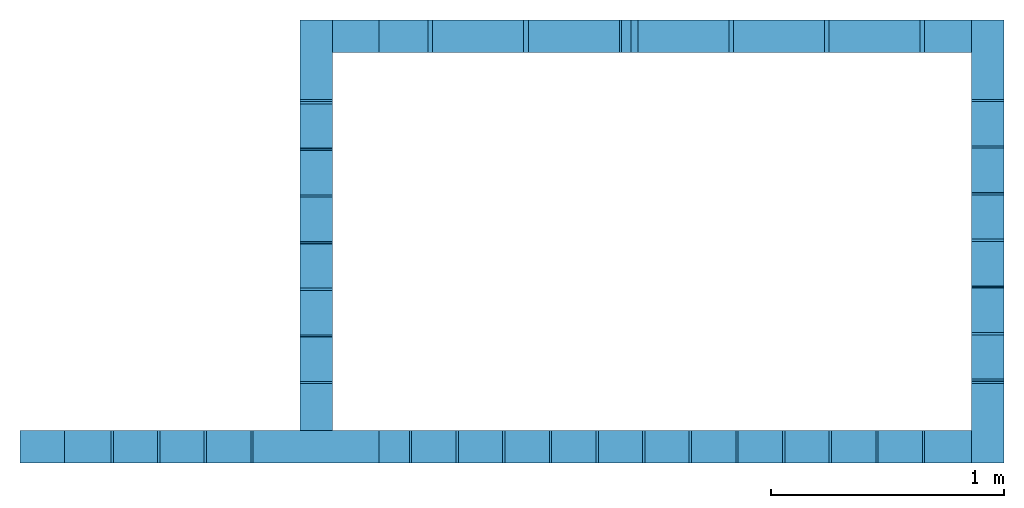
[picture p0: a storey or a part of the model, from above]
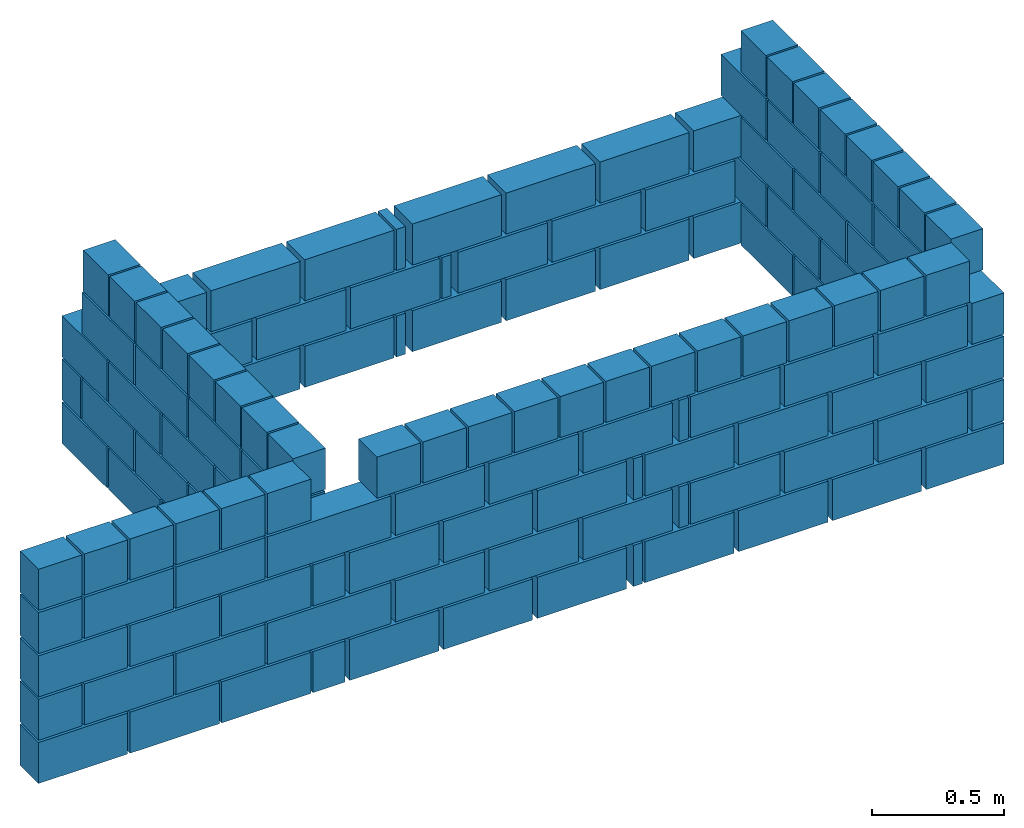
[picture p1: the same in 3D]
Properties of the parts of a building model (IFC4)

# File
Description: IFC4
Time: 2022-03-09T15:24:39
Made in: IfcPlusPlus

# IfcBuildingStorey (4)
Name | LongName | Elevation (cm)
PISO | PISO | 0
LAJE | LAJE | 272
RESP1 | RESP1 | 372
RESP2 | RESP2 | 432

# IfcWall (99)
Name | In | Armaduras - Aço CA50 - ø10.0mm | Argamassas e Grautes - Argamassa de assentamento - 3MPa (m3) | Argamassas e Grautes - Graute - 15MPa (m3) | Blocos de concreto - Classe B - Família 14x39x19 - 4MPa - Inteiro - 14x39x19
19 x  | PISO | 1
3 x  | PISO | Pset_AltoQi_QiBuilder-Itens_Associados - Description: Lista de insumos associados ao elemento
PAR-PISO-1 | PISO | 1 | 0.03616 | 0.057017 | 18 | Pset_AltoQi_QiBuilder-Itens_Associados - Armaduras - Aço CA50 - ø8.0mm: 1; Blocos de concreto - Classe B - Família 14x39x19 - 4MPa - Contrafiamento "L" - 14x34x19: 6; Blocos de concreto - Classe B - Família 14x39x19 - 4MPa - Meio Canaleta J Alto - 14x19x31x19: 4; Blocos de concreto - Classe B - Família 14x39x19 - 4MPa - Meio bloco - 14x19x19: 6
PAR-PISO-1 | PISO |  | 0.010368 | 0.046106 | Pset_AltoQi_QiBuilder-Itens_Associados - Blocos de concreto - Classe B - Família 14x39x19 - 4MPa - Meio Canaleta J Alto - 14x19x31x19: 9; Blocos de concreto - Classe B - Família 14x39x19 - 4MPa - Meio bloco - 14x19x19: 6; Blocos de concreto - Classe B - Família 14x39x19 - 4MPa - Pastilha - 14x04x19: 6
PAR-PISO-10 | PISO |  | 0.089728 | 0.14329 | 29 | Pset_AltoQi_QiBuilder-Itens_Associados - Armaduras - Aço CA50 - ø8.0mm: 1; Blocos de concreto - Classe B - Família 14x39x19 - 4MPa - Contrafiamento "L" - 14x34x19: 22; Blocos de concreto - Classe B - Família 14x39x19 - 4MPa - Meio Canaleta J Alto - 14x19x31x19: 13; Blocos de concreto - Classe B - Família 14x39x19 - 4MPa - Meio Canaleta - 14x19x19: 28; Blocos de concreto - Classe B - Família 14x39x19 - 4MPa - Pastilha - 14x09x19: 6
PAR-PISO-10 | PISO |  | 0.016 | 0.066203 | 2 | Pset_AltoQi_QiBuilder-Itens_Associados - Armaduras - Aço CA50 - ø8.0mm: 1; Blocos de concreto - Classe B - Família 14x39x19 - 4MPa - Meio Canaleta J Alto - 14x19x31x19: 5; Blocos de concreto - Classe B - Família 14x39x19 - 4MPa - Meio bloco - 14x19x19: 11; Blocos de concreto - Classe B - Família 14x39x19 - 4MPa - Meio Canaleta - 14x19x19: 5
PAR-PISO-11 | PISO |  | 0.048768 | 0.08207 | 30 | Pset_AltoQi_QiBuilder-Itens_Associados - Blocos de concreto - Classe B - Família 14x39x19 - 4MPa - Contrafiamento "L" - 14x34x19: 6; Blocos de concreto - Classe B - Família 14x39x19 - 4MPa - Meio Canaleta J Alto - 14x19x31x19: 6
PAR-PISO-11 | PISO |  | 0.14048 | 0.068193 | 96 | Pset_AltoQi_QiBuilder-Itens_Associados - Armaduras - Aço CA50 - ø8.0mm: 2; Blocos de concreto - Classe B - Família 14x39x19 - 4MPa - Contrafiamento "L" - 14x34x19: 6; Blocos de concreto - Classe B - Família 14x39x19 - 4MPa - Meio Canaleta J Alto - 14x19x31x19: 17
PAR-PISO-11 | PISO |  | 0.11232 | 0.106628 | 72 | Pset_AltoQi_QiBuilder-Itens_Associados - Blocos de concreto - Classe B - Família 14x39x19 - 4MPa - Meio Canaleta J Alto - 14x19x31x19: 14; Blocos de concreto - Classe B - Família 14x39x19 - 4MPa - Meio bloco - 14x19x19: 1; Blocos de concreto - Classe B - Família 14x39x19 - 4MPa - Contrafiamento "T" - 14x54x19: 6
PAR-PISO-11 | PISO |  | 0.03088 | 0.058396 | 6 | Pset_AltoQi_QiBuilder-Itens_Associados - Blocos de concreto - Classe B - Família 14x39x19 - 4MPa - Meio Canaleta J Alto - 14x19x31x19: 2; Blocos de concreto - Classe B - Família 14x39x19 - 4MPa - Pastilha - 14x04x19: 6; Blocos de concreto - Classe B - Família 14x39x19 - 4MPa - Pastilha - 14x09x19: 5; Blocos de concreto - Classe B - Família 14x39x19 - 4MPa - Contrafiamento "T" - 14x54x19: 11
PAR-PISO-12 | PISO |  | 0.09008 | 0.053939 | 59 | Pset_AltoQi_QiBuilder-Itens_Associados - Blocos de concreto - Classe B - Família 14x39x19 - 4MPa - Contrafiamento "L" - 14x34x19: 5; Blocos de concreto - Classe B - Família 14x39x19 - 4MPa - Meio Canaleta - 14x19x19: 14
PAR-PISO-12 | PISO |  | 0.01456 | 0.014794 | 6 | Pset_AltoQi_QiBuilder-Itens_Associados - Armaduras - Aço CA50 - ø8.0mm: 1; Blocos de concreto - Classe B - Família 14x39x19 - 4MPa - Contrafiamento "L" - 14x34x19: 5; Blocos de concreto - Classe B - Família 14x39x19 - 4MPa - Meio bloco - 14x19x19: 1; Blocos de concreto - Classe B - Família 14x39x19 - 4MPa - Meio Canaleta - 14x19x19: 1
PAR-PISO-12 | PISO |  | 0.011456 | 0.061622 | Pset_AltoQi_QiBuilder-Itens_Associados - Armaduras - Aço CA50 - ø8.0mm: 1; Blocos de concreto - Classe B - Família 14x39x19 - 4MPa - Meio bloco - 14x19x19: 6; Blocos de concreto - Classe B - Família 14x39x19 - 4MPa - Pastilha - 14x04x19: 5; Blocos de concreto - Classe B - Família 14x39x19 - 4MPa - Meio Canaleta - 14x19x19: 11
PAR-PISO-13 | PISO |  | 0.04864 | 0.026598 | 24 | Pset_AltoQi_QiBuilder-Itens_Associados - Blocos de concreto - Classe B - Família 14x39x19 - 4MPa - Contrafiamento "L" - 14x34x19: 12; Blocos de concreto - Classe B - Família 14x39x19 - 4MPa - Meio bloco - 14x19x19: 1; Blocos de concreto - Classe B - Família 14x39x19 - 4MPa - Meio Canaleta - 14x19x19: 6
PAR-PISO-13 | PISO | 1 | 0.02816 | 0.08143 | 6 | Pset_AltoQi_QiBuilder-Itens_Associados - Armaduras - Aço CA50 - ø8.0mm: 1; Blocos de concreto - Classe B - Família 14x39x19 - 4MPa - Contrafiamento "L" - 14x34x19: 6; Blocos de concreto - Classe B - Família 14x39x19 - 4MPa - Meio Canaleta J Alto - 14x19x31x19: 2; Blocos de concreto - Classe B - Família 14x39x19 - 4MPa - Pastilha - 14x04x19: 12; Blocos de concreto - Classe B - Família 14x39x19 - 4MPa - Contrafiamento "T" - 14x54x19: 6
PAR-PISO-13 | PISO |  | 0.04304 | 0.038986 | 18 | Pset_AltoQi_QiBuilder-Itens_Associados - Blocos de concreto - Classe B - Família 14x39x19 - 4MPa - Contrafiamento "L" - 14x34x19: 5; Blocos de concreto - Classe B - Família 14x39x19 - 4MPa - Meio bloco - 14x19x19: 1; Blocos de concreto - Classe B - Família 14x39x19 - 4MPa - Pastilha - 14x04x19: 11; Blocos de concreto - Classe B - Família 14x39x19 - 4MPa - Meio Canaleta - 14x19x19: 4; Blocos de concreto - Classe B - Família 14x39x19 - 4MPa - Contrafiamento "T" - 14x54x19: 5; Blocos de concreto - Classe B - Família 14x39x19 - 4MPa - Contrafiamento compensador - 14x24x19: 1
PAR-PISO-14 | PISO | 1 | 0.037888 | 0.116429 | 6 | Pset_AltoQi_QiBuilder-Itens_Associados - Armaduras - Aço CA50 - ø8.0mm: 1; Blocos de concreto - Classe B - Família 14x39x19 - 4MPa - Contrafiamento "L" - 14x34x19: 11; Blocos de concreto - Classe B - Família 14x39x19 - 4MPa - Meio bloco - 14x19x19: 11; Blocos de concreto - Classe B - Família 14x39x19 - 4MPa - Pastilha - 14x04x19: 5; Blocos de concreto - Classe B - Família 14x39x19 - 4MPa - Meio Canaleta - 14x19x19: 16
PAR-PISO-15 | PISO |  | 0.078848 | 0.132438 | 28 | Pset_AltoQi_QiBuilder-Itens_Associados - Armaduras - Aço CA50 - ø8.0mm: 1; Blocos de concreto - Classe B - Família 14x39x19 - 4MPa - Contrafiamento "L" - 14x34x19: 5; Blocos de concreto - Classe B - Família 14x39x19 - 4MPa - Meio Canaleta J Alto - 14x19x31x19: 12; Blocos de concreto - Classe B - Família 14x39x19 - 4MPa - Pastilha - 14x04x19: 6; Blocos de concreto - Classe B - Família 14x39x19 - 4MPa - Meio Canaleta - 14x19x19: 24; Blocos de concreto - Classe B - Família 14x39x19 - 4MPa - Contrafiamento "T" - 14x54x19: 5; Blocos de concreto - Classe B - Família 14x39x19 - 4MPa - Contrafiamento compensador - 14x24x19: 6
PAR-PISO-15 | PISO |  | 0.07792 | 0.134534 | 28 | Pset_AltoQi_QiBuilder-Itens_Associados - Armaduras - Aço CA50 - ø8.0mm: 3; Blocos de concreto - Classe B - Família 14x39x19 - 4MPa - Contrafiamento "L" - 14x34x19: 6; Blocos de concreto - Classe B - Família 14x39x19 - 4MPa - Meio Canaleta J Alto - 14x19x31x19: 12; Blocos de concreto - Classe B - Família 14x39x19 - 4MPa - Pastilha - 14x04x19: 6; Blocos de concreto - Classe B - Família 14x39x19 - 4MPa - Meio Canaleta - 14x19x19: 24; Blocos de concreto - Classe B - Família 14x39x19 - 4MPa - Pastilha - 14x09x19: 1; Blocos de concreto - Classe B - Família 14x39x19 - 4MPa - Contrafiamento "T" - 14x54x19: 4; Blocos de concreto - Classe B - Família 14x39x19 - 4MPa - Contrafiamento compensador - 14x24x19: 5
PAR-PISO-15 | PISO |  | 0.0512 | 0.08223 | 26 | Pset_AltoQi_QiBuilder-Itens_Associados - Armaduras - Aço CA50 - ø8.0mm: 1; Blocos de concreto - Classe B - Família 14x39x19 - 4MPa - Meio Canaleta J Alto - 14x19x31x19: 8; Blocos de concreto - Classe B - Família 14x39x19 - 4MPa - Meio bloco - 14x19x19: 3; Blocos de concreto - Classe B - Família 14x39x19 - 4MPa - Meio Canaleta - 14x19x19: 17
PAR-PISO-2 | PISO |  | 0.163648 | 0.103037 | 108 | Pset_AltoQi_QiBuilder-Itens_Associados - Armaduras - Aço CA50 - ø8.0mm: 1; Blocos de concreto - Classe B - Família 14x39x19 - 4MPa - Contrafiamento "L" - 14x34x19: 12; Blocos de concreto - Classe B - Família 14x39x19 - 4MPa - Meio Canaleta J Alto - 14x19x31x19: 19
PAR-PISO-3 | PISO |  | 0.011744 |  | 5 | Pset_AltoQi_QiBuilder-Itens_Associados - Blocos de concreto - Classe B - Família 14x39x19 - 4MPa - Contrafiamento "L" - 14x34x19: 3; Blocos de concreto - Classe B - Família 14x39x19 - 4MPa - Meio bloco - 14x19x19: 2; Blocos de concreto - Classe B - Família 14x39x19 - 4MPa - Pastilha - 14x04x19: 5
PAR-PISO-4 | PISO | 1 | 0.055776 | 0.178548 | 10 | Pset_AltoQi_QiBuilder-Itens_Associados - Armaduras - Aço CA50 - ø8.0mm: 2; Blocos de concreto - Classe B - Família 14x39x19 - 4MPa - Contrafiamento "L" - 14x34x19: 6; Blocos de concreto - Classe B - Família 14x39x19 - 4MPa - Meio bloco - 14x19x19: 14; Blocos de concreto - Classe B - Família 14x39x19 - 4MPa - Pastilha - 14x04x19: 11; Blocos de concreto - Classe B - Família 14x39x19 - 4MPa - Meio Canaleta - 14x19x19: 35; Blocos de concreto - Classe B - Família 14x39x19 - 4MPa - Pastilha - 14x09x19: 3; Blocos de concreto - Classe B - Família 14x39x19 - 4MPa - Contrafiamento compensador - 14x24x19: 3
PAR-PISO-5 | PISO |  | 0.018816 | 0.070844 | 5 | Pset_AltoQi_QiBuilder-Itens_Associados - Armaduras - Aço CA50 - ø8.0mm: 1; Blocos de concreto - Classe B - Família 14x39x19 - 4MPa - Meio bloco - 14x19x19: 6; Blocos de concreto - Classe B - Família 14x39x19 - 4MPa - Pastilha - 14x04x19: 11; Blocos de concreto - Classe B - Família 14x39x19 - 4MPa - Meio Canaleta - 14x19x19: 11
PAR-PISO-5 | PISO | 1 | 0.10768 | 0.175331 | 64 | Pset_AltoQi_QiBuilder-Itens_Associados - Armaduras - Aço CA50 - ø8.0mm: 2; Blocos de concreto - Classe B - Família 14x39x19 - 4MPa - Contrafiamento "L" - 14x34x19: 5; Blocos de concreto - Classe B - Família 14x39x19 - 4MPa - Meio bloco - 14x19x19: 1; Blocos de concreto - Classe B - Família 14x39x19 - 4MPa - Pastilha - 14x04x19: 9; Blocos de concreto - Classe B - Família 14x39x19 - 4MPa - Meio Canaleta - 14x19x19: 27; Blocos de concreto - Classe B - Família 14x39x19 - 4MPa - Contrafiamento compensador - 14x24x19: 1
PAR-PISO-6 | PISO |  | 0.01904 | 0.074906 | 5 | Pset_AltoQi_QiBuilder-Itens_Associados - Armaduras - Aço CA50 - ø8.0mm: 2; Blocos de concreto - Classe B - Família 14x39x19 - 4MPa - Meio bloco - 14x19x19: 6; Blocos de concreto - Classe B - Família 14x39x19 - 4MPa - Pastilha - 14x04x19: 11; Blocos de concreto - Classe B - Família 14x39x19 - 4MPa - Meio Canaleta - 14x19x19: 11
PAR-PISO-6 | PISO | 1 | 0.109568 | 0.134617 | 72 | Pset_AltoQi_QiBuilder-Itens_Associados - Blocos de concreto - Classe B - Família 14x39x19 - 4MPa - Contrafiamento "L" - 14x34x19: 6; Blocos de concreto - Classe B - Família 14x39x19 - 4MPa - Pastilha - 14x04x19: 12; Blocos de concreto - Classe B - Família 14x39x19 - 4MPa - Meio Canaleta - 14x19x19: 14
PAR-PISO-7 | PISO |  | 0.035776 | 0.025324 | 18 | Pset_AltoQi_QiBuilder-Itens_Associados - Armaduras - Aço CA50 - ø8.0mm: 1; Blocos de concreto - Classe B - Família 14x39x19 - 4MPa - Contrafiamento "L" - 14x34x19: 6; Blocos de concreto - Classe B - Família 14x39x19 - 4MPa - Meio bloco - 14x19x19: 6; Blocos de concreto - Classe B - Família 14x39x19 - 4MPa - Meio Canaleta - 14x19x19: 4
PAR-PISO-8 | PISO |  | 0.01344 |  | 8 | Pset_AltoQi_QiBuilder-Itens_Associados - Blocos de concreto - Classe B - Família 14x39x19 - 4MPa - Meio bloco - 14x19x19: 2; Blocos de concreto - Classe B - Família 14x39x19 - 4MPa - Pastilha - 14x04x19: 3; Blocos de concreto - Classe B - Família 14x39x19 - 4MPa - Contrafiamento compensador - 14x24x19: 2
PAR-PISO-9 | PISO | 1 | 0.13536 | 0.09114 | 72 | Pset_AltoQi_QiBuilder-Itens_Associados - Armaduras - Aço CA50 - ø8.0mm: 1; Blocos de concreto - Classe B - Família 14x39x19 - 4MPa - Contrafiamento "L" - 14x34x19: 30; Blocos de concreto - Classe B - Família 14x39x19 - 4MPa - Meio Canaleta J Alto - 14x19x31x19: 15
PAR-PISO-9 | PISO |  | 0.032128 | 0.029051 | 18 | Pset_AltoQi_QiBuilder-Itens_Associados - Blocos de concreto - Classe B - Família 14x39x19 - 4MPa - Contrafiamento "L" - 14x34x19: 6; Blocos de concreto - Classe B - Família 14x39x19 - 4MPa - Meio Canaleta - 14x19x19: 4
9 x  | LAJE | 1
2 x  | LAJE | Pset_AltoQi_QiBuilder-Itens_Associados - Description: Lista de insumos associados ao elemento
PAR-LAJE-1 | LAJE |  | 0.044096 | 0.059454 | 24 | Pset_AltoQi_QiBuilder-Itens_Associados - Armaduras - Aço CA50 - ø8.0mm: 1; Blocos de concreto - Classe B - Família 14x39x19 - 4MPa - Contrafiamento "L" - 14x34x19: 4; Blocos de concreto - Classe B - Família 14x39x19 - 4MPa - Pastilha - 14x04x19: 4; Blocos de concreto - Classe B - Família 14x39x19 - 4MPa - Meio Canaleta - 14x19x19: 13
PAR-LAJE-2 | LAJE |  | 0.041856 | 0.04925 | 24 | Pset_AltoQi_QiBuilder-Itens_Associados - Blocos de concreto - Classe B - Família 14x39x19 - 4MPa - Contrafiamento "L" - 14x34x19: 2; Blocos de concreto - Classe B - Família 14x39x19 - 4MPa - Pastilha - 14x04x19: 4; Blocos de concreto - Classe B - Família 14x39x19 - 4MPa - Meio Canaleta - 14x19x19: 13
PAR-LAJE-2 | LAJE |  | 0.0192 | 0.034643 | 8 | Pset_AltoQi_QiBuilder-Itens_Associados - Armaduras - Aço CA50 - ø8.0mm: 1; Blocos de concreto - Classe B - Família 14x39x19 - 4MPa - Contrafiamento "L" - 14x34x19: 2; Blocos de concreto - Classe B - Família 14x39x19 - 4MPa - Meio Canaleta - 14x19x19: 5; Blocos de concreto - Classe B - Família 14x39x19 - 4MPa - Contrafiamento "T" - 14x54x19: 2
PAR-LAJE-3 | LAJE |  | 0.064896 | 0.079325 | 38 | Pset_AltoQi_QiBuilder-Itens_Associados - Armaduras - Aço CA50 - ø8.0mm: 1; Blocos de concreto - Classe B - Família 14x39x19 - 4MPa - Contrafiamento "L" - 14x34x19: 2; Blocos de concreto - Classe B - Família 14x39x19 - 4MPa - Meio bloco - 14x19x19: 2; Blocos de concreto - Classe B - Família 14x39x19 - 4MPa - Meio Canaleta - 14x19x19: 20
PAR-LAJE-4 | LAJE |  | 0.043456 | 0.05307 | 24 | Pset_AltoQi_QiBuilder-Itens_Associados - Armaduras - Aço CA50 - ø8.0mm: 1; Blocos de concreto - Classe B - Família 14x39x19 - 4MPa - Contrafiamento "L" - 14x34x19: 4; Blocos de concreto - Classe B - Família 14x39x19 - 4MPa - Meio Canaleta - 14x19x19: 13
PAR-LAJE-5 | LAJE | 1 | 0.138432 | 0.169733 | 84 | Pset_AltoQi_QiBuilder-Itens_Associados - Armaduras - Aço CA50 - ø8.0mm: 1; Blocos de concreto - Classe B - Família 14x39x19 - 4MPa - Contrafiamento "L" - 14x34x19: 2; Blocos de concreto - Classe B - Família 14x39x19 - 4MPa - Meio bloco - 14x19x19: 2; Blocos de concreto - Classe B - Família 14x39x19 - 4MPa - Meio Canaleta - 14x19x19: 43
PAR-LAJE-6 | LAJE |  | 0.0192 | 0.029576 | 8 | Pset_AltoQi_QiBuilder-Itens_Associados - Armaduras - Aço CA50 - ø8.0mm: 1; Blocos de concreto - Classe B - Família 14x39x19 - 4MPa - Contrafiamento "L" - 14x34x19: 2; Blocos de concreto - Classe B - Família 14x39x19 - 4MPa - Meio Canaleta - 14x19x19: 5; Blocos de concreto - Classe B - Família 14x39x19 - 4MPa - Contrafiamento "T" - 14x54x19: 2
PAR-LAJE-6 | LAJE |  | 0.038016 | 0.043139 | 22 | Pset_AltoQi_QiBuilder-Itens_Associados - Blocos de concreto - Classe B - Família 14x39x19 - 4MPa - Contrafiamento "L" - 14x34x19: 2; Blocos de concreto - Classe B - Família 14x39x19 - 4MPa - Meio Canaleta - 14x19x19: 12
PAR-LAJE-7 | LAJE |  | 0.027456 | 0.03822 | 14 | Pset_AltoQi_QiBuilder-Itens_Associados - Armaduras - Aço CA50 - ø8.0mm: 1; Blocos de concreto - Classe B - Família 14x39x19 - 4MPa - Contrafiamento "L" - 14x34x19: 4; Blocos de concreto - Classe B - Família 14x39x19 - 4MPa - Meio Canaleta - 14x19x19: 8
PAR-LAJE-8 | LAJE |  | 0.04064 | 0.059894 | 22 | Pset_AltoQi_QiBuilder-Itens_Associados - Armaduras - Aço CA50 - ø8.0mm: 1; Blocos de concreto - Classe B - Família 14x39x19 - 4MPa - Meio bloco - 14x19x19: 2; Blocos de concreto - Classe B - Família 14x39x19 - 4MPa - Meio Canaleta - 14x19x19: 12; Blocos de concreto - Classe B - Família 14x39x19 - 4MPa - Contrafiamento "T" - 14x54x19: 2
PAR-LAJE-8 | LAJE | 1 | 0.016576 | 0.049898 | 4 | Pset_AltoQi_QiBuilder-Itens_Associados - Blocos de concreto - Classe B - Família 14x39x19 - 4MPa - Contrafiamento "L" - 14x34x19: 4; Blocos de concreto - Classe B - Família 14x39x19 - 4MPa - Meio bloco - 14x19x19: 2; Blocos de concreto - Classe B - Família 14x39x19 - 4MPa - Meio Canaleta - 14x19x19: 8; Blocos de concreto - Classe B - Família 14x39x19 - 4MPa - Pastilha - 14x09x19: 2
8 x  | RESP1 | 1
PAR-RESP1-1 | RESP1 |  | 0.026208 | 0.054618 | 12 | Pset_AltoQi_QiBuilder-Itens_Associados - Armaduras - Aço CA50 - ø8.0mm: 1; Blocos de concreto - Classe B - Família 14x39x19 - 4MPa - Contrafiamento "L" - 14x34x19: 2; Blocos de concreto - Classe B - Família 14x39x19 - 4MPa - Pastilha - 14x04x19: 2; Blocos de concreto - Classe B - Família 14x39x19 - 4MPa - Meio Canaleta - 14x19x19: 13
PAR-RESP1-2 | RESP1 |  | 0.02512 | 0.052998 | 12 | Pset_AltoQi_QiBuilder-Itens_Associados - Armaduras - Aço CA50 - ø8.0mm: 1; Blocos de concreto - Classe B - Família 14x39x19 - 4MPa - Contrafiamento "L" - 14x34x19: 1; Blocos de concreto - Classe B - Família 14x39x19 - 4MPa - Pastilha - 14x04x19: 2; Blocos de concreto - Classe B - Família 14x39x19 - 4MPa - Meio Canaleta - 14x19x19: 13
PAR-RESP1-2 | RESP1 |  | 0.011168 | 0.025546 | 4 | Pset_AltoQi_QiBuilder-Itens_Associados - Blocos de concreto - Classe B - Família 14x39x19 - 4MPa - Contrafiamento "L" - 14x34x19: 1; Blocos de concreto - Classe B - Família 14x39x19 - 4MPa - Meio Canaleta - 14x19x19: 5; Blocos de concreto - Classe B - Família 14x39x19 - 4MPa - Contrafiamento "T" - 14x54x19: 1
PAR-RESP1-3 | RESP1 |  | 0.025888 | 0.04983 | 12 | Pset_AltoQi_QiBuilder-Itens_Associados - Armaduras - Aço CA50 - ø8.0mm: 1; Blocos de concreto - Classe B - Família 14x39x19 - 4MPa - Contrafiamento "L" - 14x34x19: 2; Blocos de concreto - Classe B - Família 14x39x19 - 4MPa - Meio Canaleta - 14x19x19: 13
PAR-RESP1-4 | RESP1 |  | 0.033376 | 0.06804 | 16 | Pset_AltoQi_QiBuilder-Itens_Associados - Armaduras - Aço CA50 - ø8.0mm: 1; Blocos de concreto - Classe B - Família 14x39x19 - 4MPa - Contrafiamento "L" - 14x34x19: 1; Blocos de concreto - Classe B - Família 14x39x19 - 4MPa - Meio bloco - 14x19x19: 1; Blocos de concreto - Classe B - Família 14x39x19 - 4MPa - Pastilha - 14x04x19: 2; Blocos de concreto - Classe B - Família 14x39x19 - 4MPa - Meio Canaleta - 14x19x19: 17
PAR-RESP1-5 | RESP1 |  | 0.034208 | 0.066235 | 16 | Pset_AltoQi_QiBuilder-Itens_Associados - Armaduras - Aço CA50 - ø8.0mm: 1; Blocos de concreto - Classe B - Família 14x39x19 - 4MPa - Contrafiamento "L" - 14x34x19: 2; Blocos de concreto - Classe B - Família 14x39x19 - 4MPa - Meio Canaleta - 14x19x19: 17; Blocos de concreto - Classe B - Família 14x39x19 - 4MPa - Pastilha - 14x09x19: 2
PAR-RESP1-6 | RESP1 |  | 0.016288 | 0.03498 | 7 | Pset_AltoQi_QiBuilder-Itens_Associados - Armaduras - Aço CA50 - ø8.0mm: 1; Blocos de concreto - Classe B - Família 14x39x19 - 4MPa - Contrafiamento "L" - 14x34x19: 2; Blocos de concreto - Classe B - Família 14x39x19 - 4MPa - Meio Canaleta - 14x19x19: 8
PAR-RESP1-7 | RESP1 |  | 0.016288 | 0.03498 | 7 | Pset_AltoQi_QiBuilder-Itens_Associados - Armaduras - Aço CA50 - ø8.0mm: 1; Blocos de concreto - Classe B - Família 14x39x19 - 4MPa - Contrafiamento "L" - 14x34x19: 2; Blocos de concreto - Classe B - Família 14x39x19 - 4MPa - Meio Canaleta - 14x19x19: 8
5 x  | RESP2 | 1
PAR-RESP2-1 | RESP2 |  | 0.026816 |  | 18 | Pset_AltoQi_QiBuilder-Itens_Associados - Blocos de concreto - Classe B - Família 14x39x19 - 4MPa - Contrafiamento "L" - 14x34x19: 3; Blocos de concreto - Classe B - Família 14x39x19 - 4MPa - Pastilha - 14x04x19: 3
PAR-RESP2-2 | RESP2 |  | 0.04192 | 0.056214 | 24 | Pset_AltoQi_QiBuilder-Itens_Associados - Armaduras - Aço CA50 - ø8.0mm: 1; Blocos de concreto - Classe B - Família 14x39x19 - 4MPa - Contrafiamento "L" - 14x34x19: 2; Blocos de concreto - Classe B - Família 14x39x19 - 4MPa - Pastilha - 14x04x19: 4; Blocos de concreto - Classe B - Família 14x39x19 - 4MPa - Meio Canaleta - 14x19x19: 13
PAR-RESP2-2 | RESP2 |  | 0.021312 | 0.031624 | 10 | Pset_AltoQi_QiBuilder-Itens_Associados - Blocos de concreto - Classe B - Família 14x39x19 - 4MPa - Meio bloco - 14x19x19: 2; Blocos de concreto - Classe B - Família 14x39x19 - 4MPa - Meio Canaleta - 14x19x19: 6; Blocos de concreto - Classe B - Família 14x39x19 - 4MPa - Contrafiamento "T" - 14x54x19: 2
PAR-RESP2-3 | RESP2 |  | 0.027456 | 0.04214 | 14 | Pset_AltoQi_QiBuilder-Itens_Associados - Armaduras - Aço CA50 - ø8.0mm: 1; Blocos de concreto - Classe B - Família 14x39x19 - 4MPa - Contrafiamento "L" - 14x34x19: 4; Blocos de concreto - Classe B - Família 14x39x19 - 4MPa - Meio Canaleta - 14x19x19: 8
PAR-RESP2-4 | RESP2 |  | 0.027456 | 0.03822 | 14 | Pset_AltoQi_QiBuilder-Itens_Associados - Armaduras - Aço CA50 - ø8.0mm: 1; Blocos de concreto - Classe B - Família 14x39x19 - 4MPa - Contrafiamento "L" - 14x34x19: 4; Blocos de concreto - Classe B - Família 14x39x19 - 4MPa - Meio Canaleta - 14x19x19: 8
